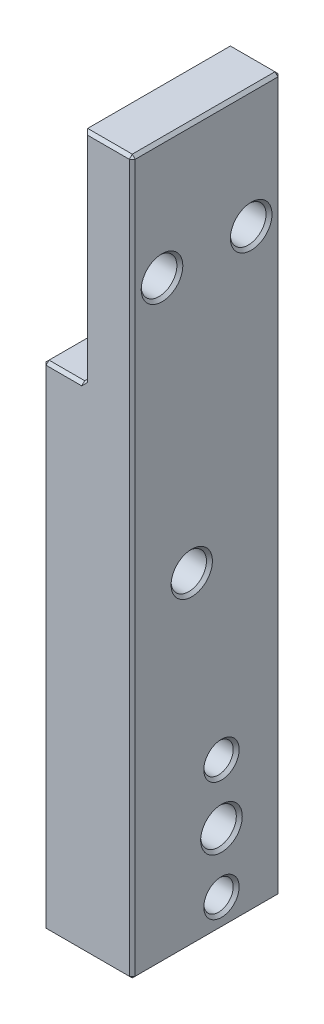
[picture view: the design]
ISO-10303-21;
HEADER;
FILE_DESCRIPTION(('STEP AP214'),'2;1');
FILE_NAME('part.step','',(''),(''),'','','');
FILE_SCHEMA(('AUTOMOTIVE_DESIGN { 1 0 10303 214 1 1 1 1 }'));
ENDSEC;
DATA;
#1=APPLICATION_CONTEXT('core data for automotive mechanical design processes');
#2=APPLICATION_PROTOCOL_DEFINITION('international standard','automotive_design',2000,#1);
#3=PRODUCT_CONTEXT('',#1,'mechanical');
#4=PRODUCT('Part','Part','',(#3));
#5=PRODUCT_RELATED_PRODUCT_CATEGORY('part','',(#4));
#6=PRODUCT_DEFINITION_FORMATION('','',#4);
#7=PRODUCT_DEFINITION_CONTEXT('part definition',#1,'design');
#8=PRODUCT_DEFINITION('design','',#6,#7);
#9=PRODUCT_DEFINITION_SHAPE('','',#8);
#10=(LENGTH_UNIT() NAMED_UNIT(*) SI_UNIT(.MILLI.,.METRE.));
#11=(NAMED_UNIT(*) PLANE_ANGLE_UNIT() SI_UNIT($,.RADIAN.));
#12=(NAMED_UNIT(*) SI_UNIT($,.STERADIAN.) SOLID_ANGLE_UNIT());
#13=UNCERTAINTY_MEASURE_WITH_UNIT(LENGTH_MEASURE(1.E-05),#10,'distance_accuracy_value','');
#14=(GEOMETRIC_REPRESENTATION_CONTEXT(3) GLOBAL_UNCERTAINTY_ASSIGNED_CONTEXT((#13)) GLOBAL_UNIT_ASSIGNED_CONTEXT((#10,
#11,#12)) REPRESENTATION_CONTEXT('',''));
#15=CARTESIAN_POINT('',(0.,0.,0.));
#16=DIRECTION('',(0.,0.,1.));
#17=DIRECTION('',(1.,0.,0.));
#18=AXIS2_PLACEMENT_3D('',#15,#16,#17);
#19=CARTESIAN_POINT('',(0.,0.,25.));
#20=DIRECTION('',(-1.,0.,0.));
#21=DIRECTION('',(0.,0.,1.));
#22=AXIS2_PLACEMENT_3D('',#19,#20,#21);
#23=PLANE('',#22);
#24=CARTESIAN_POINT('',(0.,54.5,15.));
#25=DIRECTION('',(-1.,0.,0.));
#26=DIRECTION('',(0.,0.,1.));
#27=AXIS2_PLACEMENT_3D('',#24,#25,#26);
#28=CIRCLE('',#27,3.475);
#29=CARTESIAN_POINT('',(0.,54.5,18.475));
#30=VERTEX_POINT('',#29);
#31=EDGE_CURVE('E311',#30,#30,#28,.F.);
#32=ORIENTED_EDGE('',*,*,#31,.T.);
#33=EDGE_LOOP('',(#32));
#34=FACE_BOUND('',#33,.T.);
#35=CARTESIAN_POINT('',(0.,24.8,10.));
#36=DIRECTION('',(-1.,0.,0.));
#37=DIRECTION('',(0.,0.,1.));
#38=AXIS2_PLACEMENT_3D('',#35,#36,#37);
#39=CIRCLE('',#38,2.975);
#40=CARTESIAN_POINT('',(0.,24.8,12.975));
#41=VERTEX_POINT('',#40);
#42=EDGE_CURVE('E308',#41,#41,#39,.F.);
#43=ORIENTED_EDGE('',*,*,#42,.T.);
#44=EDGE_LOOP('',(#43));
#45=FACE_BOUND('',#44,.T.);
#46=CARTESIAN_POINT('',(0.,14.8,10.));
#47=DIRECTION('',(-1.,0.,0.));
#48=DIRECTION('',(0.,0.,1.));
#49=AXIS2_PLACEMENT_3D('',#46,#47,#48);
#50=CIRCLE('',#49,3.5);
#51=CARTESIAN_POINT('',(0.,14.8,13.5));
#52=VERTEX_POINT('',#51);
#53=EDGE_CURVE('E305',#52,#52,#50,.F.);
#54=ORIENTED_EDGE('',*,*,#53,.T.);
#55=EDGE_LOOP('',(#54));
#56=FACE_BOUND('',#55,.T.);
#57=CARTESIAN_POINT('',(0.,4.8,10.));
#58=DIRECTION('',(-1.,0.,0.));
#59=DIRECTION('',(0.,0.,1.));
#60=AXIS2_PLACEMENT_3D('',#57,#58,#59);
#61=CIRCLE('',#60,2.975);
#62=CARTESIAN_POINT('',(0.,4.8,12.975));
#63=VERTEX_POINT('',#62);
#64=EDGE_CURVE('E302',#63,#63,#61,.F.);
#65=ORIENTED_EDGE('',*,*,#64,.T.);
#66=EDGE_LOOP('',(#65));
#67=FACE_BOUND('',#66,.T.);
#68=DIRECTION('',(0.,-1.,0.));
#69=VECTOR('',#68,1.);
#70=CARTESIAN_POINT('',(0.,0.,0.500000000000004));
#71=LINE('',#70,#69);
#72=CARTESIAN_POINT('',(0.,82.5,0.500000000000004));
#73=VERTEX_POINT('',#72);
#74=CARTESIAN_POINT('',(0.,0.500000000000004,0.500000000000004));
#75=VERTEX_POINT('',#74);
#76=EDGE_CURVE('E297',#73,#75,#71,.T.);
#77=ORIENTED_EDGE('',*,*,#76,.T.);
#78=DIRECTION('',(0.,0.,1.));
#79=VECTOR('',#78,1.);
#80=CARTESIAN_POINT('',(0.,0.500000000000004,25.));
#81=LINE('',#80,#79);
#82=CARTESIAN_POINT('',(0.,0.500000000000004,24.5));
#83=VERTEX_POINT('',#82);
#84=EDGE_CURVE('E300',#75,#83,#81,.T.);
#85=ORIENTED_EDGE('',*,*,#84,.T.);
#86=DIRECTION('',(0.,1.,0.));
#87=VECTOR('',#86,1.);
#88=CARTESIAN_POINT('',(0.,0.,24.5));
#89=LINE('',#88,#87);
#90=CARTESIAN_POINT('',(0.,82.5,24.5));
#91=VERTEX_POINT('',#90);
#92=EDGE_CURVE('E295',#83,#91,#89,.T.);
#93=ORIENTED_EDGE('',*,*,#92,.T.);
#94=DIRECTION('',(0.,0.,-1.));
#95=VECTOR('',#94,1.);
#96=CARTESIAN_POINT('',(0.,82.5,0.));
#97=LINE('',#96,#95);
#98=EDGE_CURVE('E293',#91,#73,#97,.T.);
#99=ORIENTED_EDGE('',*,*,#98,.T.);
#100=EDGE_LOOP('',(#77,#85,#93,#99));
#101=FACE_BOUND('',#100,.T.);
#102=ADVANCED_FACE('F34',(#34,#45,#56,#67,#101),#23,.T.);
#103=CARTESIAN_POINT('',(0.,0.,25.));
#104=DIRECTION('',(0.,1.,0.));
#105=DIRECTION('',(0.,0.,1.));
#106=AXIS2_PLACEMENT_3D('',#103,#104,#105);
#107=PLANE('',#106);
#108=DIRECTION('',(1.,0.,0.));
#109=VECTOR('',#108,1.);
#110=CARTESIAN_POINT('',(0.,0.,0.500000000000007));
#111=LINE('',#110,#109);
#112=CARTESIAN_POINT('',(0.500000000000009,0.,0.500000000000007));
#113=VERTEX_POINT('',#112);
#114=CARTESIAN_POINT('',(14.5,0.,0.500000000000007));
#115=VERTEX_POINT('',#114);
#116=EDGE_CURVE('E219',#113,#115,#111,.T.);
#117=ORIENTED_EDGE('',*,*,#116,.T.);
#118=DIRECTION('',(0.,0.,1.));
#119=VECTOR('',#118,1.);
#120=CARTESIAN_POINT('',(14.5,0.,25.));
#121=LINE('',#120,#119);
#122=CARTESIAN_POINT('',(14.5,0.,24.5));
#123=VERTEX_POINT('',#122);
#124=EDGE_CURVE('E166',#115,#123,#121,.T.);
#125=ORIENTED_EDGE('',*,*,#124,.T.);
#126=DIRECTION('',(-1.,0.,0.));
#127=VECTOR('',#126,1.);
#128=CARTESIAN_POINT('',(0.,0.,24.5));
#129=LINE('',#128,#127);
#130=CARTESIAN_POINT('',(0.500000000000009,0.,24.5));
#131=VERTEX_POINT('',#130);
#132=EDGE_CURVE('E221',#123,#131,#129,.T.);
#133=ORIENTED_EDGE('',*,*,#132,.T.);
#134=DIRECTION('',(0.,0.,-1.));
#135=VECTOR('',#134,1.);
#136=CARTESIAN_POINT('',(0.500000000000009,0.,0.));
#137=LINE('',#136,#135);
#138=EDGE_CURVE('E217',#131,#113,#137,.T.);
#139=ORIENTED_EDGE('',*,*,#138,.T.);
#140=EDGE_LOOP('',(#117,#125,#133,#139));
#141=FACE_BOUND('',#140,.T.);
#142=ADVANCED_FACE('F36',(#141),#107,.F.);
#143=CARTESIAN_POINT('',(15.,120.,25.));
#144=DIRECTION('',(1.,0.,0.));
#145=DIRECTION('',(0.,1.,0.));
#146=AXIS2_PLACEMENT_3D('',#143,#144,#145);
#147=PLANE('',#146);
#148=CARTESIAN_POINT('',(15.,100.,20.));
#149=DIRECTION('',(1.,0.,0.));
#150=DIRECTION('',(0.,1.,0.));
#151=AXIS2_PLACEMENT_3D('',#148,#149,#150);
#152=CIRCLE('',#151,3.5);
#153=CARTESIAN_POINT('',(15.,103.5,20.));
#154=VERTEX_POINT('',#153);
#155=EDGE_CURVE('E214',#154,#154,#152,.F.);
#156=ORIENTED_EDGE('',*,*,#155,.T.);
#157=EDGE_LOOP('',(#156));
#158=FACE_BOUND('',#157,.T.);
#159=CARTESIAN_POINT('',(15.,100.,5.));
#160=DIRECTION('',(1.,0.,0.));
#161=DIRECTION('',(0.,1.,0.));
#162=AXIS2_PLACEMENT_3D('',#159,#160,#161);
#163=CIRCLE('',#162,3.5);
#164=CARTESIAN_POINT('',(15.,103.5,5.));
#165=VERTEX_POINT('',#164);
#166=EDGE_CURVE('E211',#165,#165,#163,.F.);
#167=ORIENTED_EDGE('',*,*,#166,.T.);
#168=EDGE_LOOP('',(#167));
#169=FACE_BOUND('',#168,.T.);
#170=CARTESIAN_POINT('',(15.,54.5,15.));
#171=DIRECTION('',(1.,0.,0.));
#172=DIRECTION('',(0.,1.,0.));
#173=AXIS2_PLACEMENT_3D('',#170,#171,#172);
#174=CIRCLE('',#173,3.47500000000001);
#175=CARTESIAN_POINT('',(15.,57.975,15.));
#176=VERTEX_POINT('',#175);
#177=EDGE_CURVE('E208',#176,#176,#174,.F.);
#178=ORIENTED_EDGE('',*,*,#177,.T.);
#179=EDGE_LOOP('',(#178));
#180=FACE_BOUND('',#179,.T.);
#181=CARTESIAN_POINT('',(15.,24.8,10.));
#182=DIRECTION('',(1.,0.,0.));
#183=DIRECTION('',(0.,1.,0.));
#184=AXIS2_PLACEMENT_3D('',#181,#182,#183);
#185=CIRCLE('',#184,2.97500000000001);
#186=CARTESIAN_POINT('',(15.,27.775,10.));
#187=VERTEX_POINT('',#186);
#188=EDGE_CURVE('E205',#187,#187,#185,.F.);
#189=ORIENTED_EDGE('',*,*,#188,.T.);
#190=EDGE_LOOP('',(#189));
#191=FACE_BOUND('',#190,.T.);
#192=CARTESIAN_POINT('',(15.,14.8,10.));
#193=DIRECTION('',(1.,0.,0.));
#194=DIRECTION('',(0.,1.,0.));
#195=AXIS2_PLACEMENT_3D('',#192,#193,#194);
#196=CIRCLE('',#195,3.50000000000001);
#197=CARTESIAN_POINT('',(15.,18.3,10.));
#198=VERTEX_POINT('',#197);
#199=EDGE_CURVE('E202',#198,#198,#196,.F.);
#200=ORIENTED_EDGE('',*,*,#199,.T.);
#201=EDGE_LOOP('',(#200));
#202=FACE_BOUND('',#201,.T.);
#203=CARTESIAN_POINT('',(15.,4.8,10.));
#204=DIRECTION('',(1.,0.,0.));
#205=DIRECTION('',(0.,1.,0.));
#206=AXIS2_PLACEMENT_3D('',#203,#204,#205);
#207=CIRCLE('',#206,2.975);
#208=CARTESIAN_POINT('',(15.,7.775,10.));
#209=VERTEX_POINT('',#208);
#210=EDGE_CURVE('E196',#209,#209,#207,.F.);
#211=ORIENTED_EDGE('',*,*,#210,.T.);
#212=EDGE_LOOP('',(#211));
#213=FACE_BOUND('',#212,.T.);
#214=DIRECTION('',(0.,0.,1.));
#215=VECTOR('',#214,1.);
#216=CARTESIAN_POINT('',(15.,119.5,25.));
#217=LINE('',#216,#215);
#218=CARTESIAN_POINT('',(15.,119.5,0.500000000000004));
#219=VERTEX_POINT('',#218);
#220=CARTESIAN_POINT('',(15.,119.5,24.5));
#221=VERTEX_POINT('',#220);
#222=EDGE_CURVE('E188',#219,#221,#217,.T.);
#223=ORIENTED_EDGE('',*,*,#222,.T.);
#224=DIRECTION('',(0.,-1.,0.));
#225=VECTOR('',#224,1.);
#226=CARTESIAN_POINT('',(15.,120.,24.5));
#227=LINE('',#226,#225);
#228=CARTESIAN_POINT('',(15.,0.500000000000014,24.5));
#229=VERTEX_POINT('',#228);
#230=EDGE_CURVE('E193',#221,#229,#227,.T.);
#231=ORIENTED_EDGE('',*,*,#230,.T.);
#232=DIRECTION('',(0.,0.,-1.));
#233=VECTOR('',#232,1.);
#234=CARTESIAN_POINT('',(15.,0.500000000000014,0.));
#235=LINE('',#234,#233);
#236=CARTESIAN_POINT('',(15.,0.500000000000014,0.500000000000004));
#237=VERTEX_POINT('',#236);
#238=EDGE_CURVE('E164',#229,#237,#235,.T.);
#239=ORIENTED_EDGE('',*,*,#238,.T.);
#240=DIRECTION('',(0.,1.,0.));
#241=VECTOR('',#240,1.);
#242=CARTESIAN_POINT('',(15.,120.,0.500000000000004));
#243=LINE('',#242,#241);
#244=EDGE_CURVE('E182',#237,#219,#243,.T.);
#245=ORIENTED_EDGE('',*,*,#244,.T.);
#246=EDGE_LOOP('',(#223,#231,#239,#245));
#247=FACE_BOUND('',#246,.T.);
#248=ADVANCED_FACE('F191',(#158,#169,#180,#191,#202,#213,#247),#147,.T.);
#249=CARTESIAN_POINT('',(7.00000000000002,120.,25.));
#250=DIRECTION('',(0.,1.,0.));
#251=DIRECTION('',(0.,0.,1.));
#252=AXIS2_PLACEMENT_3D('',#249,#250,#251);
#253=PLANE('',#252);
#254=DIRECTION('',(0.,0.,-1.));
#255=VECTOR('',#254,1.);
#256=CARTESIAN_POINT('',(7.00000000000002,120.,25.));
#257=LINE('',#256,#255);
#258=CARTESIAN_POINT('',(7.00000000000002,120.,24.5));
#259=VERTEX_POINT('',#258);
#260=CARTESIAN_POINT('',(7.00000000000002,120.,0.500000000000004));
#261=VERTEX_POINT('',#260);
#262=EDGE_CURVE('E189',#259,#261,#257,.T.);
#263=ORIENTED_EDGE('',*,*,#262,.F.);
#264=DIRECTION('',(1.,0.,0.));
#265=VECTOR('',#264,1.);
#266=CARTESIAN_POINT('',(7.00000000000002,120.,24.5));
#267=LINE('',#266,#265);
#268=CARTESIAN_POINT('',(14.5,120.,24.5));
#269=VERTEX_POINT('',#268);
#270=EDGE_CURVE('E229',#259,#269,#267,.T.);
#271=ORIENTED_EDGE('',*,*,#270,.T.);
#272=DIRECTION('',(0.,0.,-1.));
#273=VECTOR('',#272,1.);
#274=CARTESIAN_POINT('',(14.5,120.,25.));
#275=LINE('',#274,#273);
#276=CARTESIAN_POINT('',(14.5,120.,0.500000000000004));
#277=VERTEX_POINT('',#276);
#278=EDGE_CURVE('E226',#269,#277,#275,.T.);
#279=ORIENTED_EDGE('',*,*,#278,.T.);
#280=DIRECTION('',(-1.,0.,0.));
#281=VECTOR('',#280,1.);
#282=CARTESIAN_POINT('',(7.00000000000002,120.,0.500000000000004));
#283=LINE('',#282,#281);
#284=EDGE_CURVE('E224',#277,#261,#283,.T.);
#285=ORIENTED_EDGE('',*,*,#284,.T.);
#286=EDGE_LOOP('',(#263,#271,#279,#285));
#287=FACE_BOUND('',#286,.T.);
#288=ADVANCED_FACE('F360',(#287),#253,.T.);
#289=CARTESIAN_POINT('',(7.00000000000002,83.,25.));
#290=DIRECTION('',(-1.,0.,0.));
#291=DIRECTION('',(0.,0.,1.));
#292=AXIS2_PLACEMENT_3D('',#289,#290,#291);
#293=PLANE('',#292);
#294=CARTESIAN_POINT('',(7.00000000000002,100.,20.));
#295=DIRECTION('',(-1.,0.,0.));
#296=DIRECTION('',(0.,0.,1.));
#297=AXIS2_PLACEMENT_3D('',#294,#295,#296);
#298=CIRCLE('',#297,3.5);
#299=CARTESIAN_POINT('',(7.00000000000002,100.,23.5));
#300=VERTEX_POINT('',#299);
#301=EDGE_CURVE('E11',#300,#300,#298,.F.);
#302=ORIENTED_EDGE('',*,*,#301,.T.);
#303=EDGE_LOOP('',(#302));
#304=FACE_BOUND('',#303,.T.);
#305=CARTESIAN_POINT('',(7.00000000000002,100.,5.));
#306=DIRECTION('',(-1.,0.,0.));
#307=DIRECTION('',(0.,0.,1.));
#308=AXIS2_PLACEMENT_3D('',#305,#306,#307);
#309=CIRCLE('',#308,3.);
#310=CARTESIAN_POINT('',(7.00000000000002,100.,8.));
#311=VERTEX_POINT('',#310);
#312=EDGE_CURVE('E458',#311,#311,#309,.T.);
#313=ORIENTED_EDGE('',*,*,#312,.F.);
#314=EDGE_LOOP('',(#313));
#315=FACE_BOUND('',#314,.T.);
#316=DIRECTION('',(0.,0.,1.));
#317=VECTOR('',#316,1.);
#318=CARTESIAN_POINT('',(7.00000000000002,83.5,25.));
#319=LINE('',#318,#317);
#320=CARTESIAN_POINT('',(7.00000000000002,83.5,0.500000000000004));
#321=VERTEX_POINT('',#320);
#322=CARTESIAN_POINT('',(7.00000000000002,83.5,24.5));
#323=VERTEX_POINT('',#322);
#324=EDGE_CURVE('E261',#321,#323,#319,.T.);
#325=ORIENTED_EDGE('',*,*,#324,.T.);
#326=DIRECTION('',(0.,1.,0.));
#327=VECTOR('',#326,1.);
#328=CARTESIAN_POINT('',(7.00000000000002,83.,24.5));
#329=LINE('',#328,#327);
#330=EDGE_CURVE('E265',#323,#259,#329,.T.);
#331=ORIENTED_EDGE('',*,*,#330,.T.);
#332=ORIENTED_EDGE('',*,*,#262,.T.);
#333=DIRECTION('',(0.,-1.,0.));
#334=VECTOR('',#333,1.);
#335=CARTESIAN_POINT('',(7.00000000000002,83.,0.500000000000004));
#336=LINE('',#335,#334);
#337=EDGE_CURVE('E263',#261,#321,#336,.T.);
#338=ORIENTED_EDGE('',*,*,#337,.T.);
#339=EDGE_LOOP('',(#325,#331,#332,#338));
#340=FACE_BOUND('',#339,.T.);
#341=ADVANCED_FACE('F356',(#304,#315,#340),#293,.T.);
#342=CARTESIAN_POINT('',(7.00000000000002,83.,25.));
#343=DIRECTION('',(0.,-1.,0.));
#344=DIRECTION('',(0.,0.,-1.));
#345=AXIS2_PLACEMENT_3D('',#342,#343,#344);
#346=PLANE('',#345);
#347=DIRECTION('',(-1.,0.,0.));
#348=VECTOR('',#347,1.);
#349=CARTESIAN_POINT('',(7.00000000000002,83.,0.500000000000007));
#350=LINE('',#349,#348);
#351=CARTESIAN_POINT('',(6.50000000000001,83.,0.500000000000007));
#352=VERTEX_POINT('',#351);
#353=CARTESIAN_POINT('',(0.500000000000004,83.,0.500000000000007));
#354=VERTEX_POINT('',#353);
#355=EDGE_CURVE('E49',#352,#354,#350,.T.);
#356=ORIENTED_EDGE('',*,*,#355,.T.);
#357=DIRECTION('',(0.,0.,1.));
#358=VECTOR('',#357,1.);
#359=CARTESIAN_POINT('',(0.500000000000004,83.,25.));
#360=LINE('',#359,#358);
#361=CARTESIAN_POINT('',(0.500000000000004,83.,24.5));
#362=VERTEX_POINT('',#361);
#363=EDGE_CURVE('E318',#354,#362,#360,.T.);
#364=ORIENTED_EDGE('',*,*,#363,.T.);
#365=DIRECTION('',(1.,0.,0.));
#366=VECTOR('',#365,1.);
#367=CARTESIAN_POINT('',(7.00000000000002,83.,24.5));
#368=LINE('',#367,#366);
#369=CARTESIAN_POINT('',(6.50000000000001,83.,24.5));
#370=VERTEX_POINT('',#369);
#371=EDGE_CURVE('E314',#362,#370,#368,.T.);
#372=ORIENTED_EDGE('',*,*,#371,.T.);
#373=DIRECTION('',(0.,0.,-1.));
#374=VECTOR('',#373,1.);
#375=CARTESIAN_POINT('',(6.50000000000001,83.,25.));
#376=LINE('',#375,#374);
#377=EDGE_CURVE('E54',#370,#352,#376,.T.);
#378=ORIENTED_EDGE('',*,*,#377,.T.);
#379=EDGE_LOOP('',(#356,#364,#372,#378));
#380=FACE_BOUND('',#379,.T.);
#381=ADVANCED_FACE('F353',(#380),#346,.F.);
#382=CARTESIAN_POINT('',(0.,83.,25.));
#383=DIRECTION('',(0.,0.,1.));
#384=DIRECTION('',(1.,0.,0.));
#385=AXIS2_PLACEMENT_3D('',#382,#383,#384);
#386=PLANE('',#385);
#387=DIRECTION('',(0.,-1.,0.));
#388=VECTOR('',#387,1.);
#389=CARTESIAN_POINT('',(7.50000000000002,83.,25.));
#390=LINE('',#389,#388);
#391=CARTESIAN_POINT('',(7.50000000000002,119.5,25.));
#392=VERTEX_POINT('',#391);
#393=CARTESIAN_POINT('',(7.50000000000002,83.5,25.));
#394=VERTEX_POINT('',#393);
#395=EDGE_CURVE('E277',#392,#394,#390,.T.);
#396=ORIENTED_EDGE('',*,*,#395,.T.);
#397=DIRECTION('',(0.707106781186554,0.707106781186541,0.));
#398=VECTOR('',#397,1.);
#399=CARTESIAN_POINT('',(3.49999999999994,79.5,25.));
#400=LINE('',#399,#398);
#401=CARTESIAN_POINT('',(6.50000000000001,82.5,25.));
#402=VERTEX_POINT('',#401);
#403=EDGE_CURVE('E320',#394,#402,#400,.F.);
#404=ORIENTED_EDGE('',*,*,#403,.T.);
#405=DIRECTION('',(-1.,0.,0.));
#406=VECTOR('',#405,1.);
#407=CARTESIAN_POINT('',(0.,82.5,25.));
#408=LINE('',#407,#406);
#409=CARTESIAN_POINT('',(0.500000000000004,82.5,25.));
#410=VERTEX_POINT('',#409);
#411=EDGE_CURVE('E267',#402,#410,#408,.T.);
#412=ORIENTED_EDGE('',*,*,#411,.T.);
#413=DIRECTION('',(0.,-1.,0.));
#414=VECTOR('',#413,1.);
#415=CARTESIAN_POINT('',(0.500000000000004,83.,25.));
#416=LINE('',#415,#414);
#417=CARTESIAN_POINT('',(0.500000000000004,0.500000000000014,25.));
#418=VERTEX_POINT('',#417);
#419=EDGE_CURVE('E269',#410,#418,#416,.T.);
#420=ORIENTED_EDGE('',*,*,#419,.T.);
#421=DIRECTION('',(1.,0.,0.));
#422=VECTOR('',#421,1.);
#423=CARTESIAN_POINT('',(15.,0.500000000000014,25.));
#424=LINE('',#423,#422);
#425=CARTESIAN_POINT('',(14.5,0.500000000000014,25.));
#426=VERTEX_POINT('',#425);
#427=EDGE_CURVE('E271',#418,#426,#424,.T.);
#428=ORIENTED_EDGE('',*,*,#427,.T.);
#429=DIRECTION('',(0.,1.,0.));
#430=VECTOR('',#429,1.);
#431=CARTESIAN_POINT('',(14.5,83.,25.));
#432=LINE('',#431,#430);
#433=CARTESIAN_POINT('',(14.5,119.5,25.));
#434=VERTEX_POINT('',#433);
#435=EDGE_CURVE('E273',#426,#434,#432,.T.);
#436=ORIENTED_EDGE('',*,*,#435,.T.);
#437=DIRECTION('',(-1.,0.,0.));
#438=VECTOR('',#437,1.);
#439=CARTESIAN_POINT('',(0.,119.5,25.));
#440=LINE('',#439,#438);
#441=EDGE_CURVE('E275',#434,#392,#440,.T.);
#442=ORIENTED_EDGE('',*,*,#441,.T.);
#443=EDGE_LOOP('',(#396,#404,#412,#420,#428,#436,#442));
#444=FACE_BOUND('',#443,.T.);
#445=ADVANCED_FACE('F351',(#444),#386,.T.);
#446=CARTESIAN_POINT('',(0.,83.,0.));
#447=DIRECTION('',(0.,0.,1.));
#448=DIRECTION('',(1.,0.,0.));
#449=AXIS2_PLACEMENT_3D('',#446,#447,#448);
#450=PLANE('',#449);
#451=DIRECTION('',(1.,0.,0.));
#452=VECTOR('',#451,1.);
#453=CARTESIAN_POINT('',(0.,82.5,0.));
#454=LINE('',#453,#452);
#455=CARTESIAN_POINT('',(0.500000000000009,82.5,0.));
#456=VERTEX_POINT('',#455);
#457=CARTESIAN_POINT('',(6.50000000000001,82.5,0.));
#458=VERTEX_POINT('',#457);
#459=EDGE_CURVE('E280',#456,#458,#454,.T.);
#460=ORIENTED_EDGE('',*,*,#459,.T.);
#461=DIRECTION('',(-0.707106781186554,-0.707106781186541,0.));
#462=VECTOR('',#461,1.);
#463=CARTESIAN_POINT('',(6.5,82.5,0.));
#464=LINE('',#463,#462);
#465=CARTESIAN_POINT('',(7.50000000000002,83.5,0.));
#466=VERTEX_POINT('',#465);
#467=EDGE_CURVE('E322',#458,#466,#464,.F.);
#468=ORIENTED_EDGE('',*,*,#467,.T.);
#469=DIRECTION('',(0.,1.,0.));
#470=VECTOR('',#469,1.);
#471=CARTESIAN_POINT('',(7.50000000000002,120.,0.));
#472=LINE('',#471,#470);
#473=CARTESIAN_POINT('',(7.50000000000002,119.5,0.));
#474=VERTEX_POINT('',#473);
#475=EDGE_CURVE('E291',#466,#474,#472,.T.);
#476=ORIENTED_EDGE('',*,*,#475,.T.);
#477=DIRECTION('',(1.,0.,0.));
#478=VECTOR('',#477,1.);
#479=CARTESIAN_POINT('',(15.,119.5,0.));
#480=LINE('',#479,#478);
#481=CARTESIAN_POINT('',(14.5,119.5,0.));
#482=VERTEX_POINT('',#481);
#483=EDGE_CURVE('E289',#474,#482,#480,.T.);
#484=ORIENTED_EDGE('',*,*,#483,.T.);
#485=DIRECTION('',(0.,-1.,0.));
#486=VECTOR('',#485,1.);
#487=CARTESIAN_POINT('',(14.5,0.,0.));
#488=LINE('',#487,#486);
#489=CARTESIAN_POINT('',(14.5,0.5,0.));
#490=VERTEX_POINT('',#489);
#491=EDGE_CURVE('E287',#482,#490,#488,.T.);
#492=ORIENTED_EDGE('',*,*,#491,.T.);
#493=DIRECTION('',(-1.,0.,0.));
#494=VECTOR('',#493,1.);
#495=CARTESIAN_POINT('',(0.,0.5,0.));
#496=LINE('',#495,#494);
#497=CARTESIAN_POINT('',(0.500000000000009,0.5,0.));
#498=VERTEX_POINT('',#497);
#499=EDGE_CURVE('E284',#490,#498,#496,.T.);
#500=ORIENTED_EDGE('',*,*,#499,.T.);
#501=DIRECTION('',(0.,1.,0.));
#502=VECTOR('',#501,1.);
#503=CARTESIAN_POINT('',(0.500000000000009,83.,0.));
#504=LINE('',#503,#502);
#505=EDGE_CURVE('E282',#498,#456,#504,.T.);
#506=ORIENTED_EDGE('',*,*,#505,.T.);
#507=EDGE_LOOP('',(#460,#468,#476,#484,#492,#500,#506));
#508=FACE_BOUND('',#507,.T.);
#509=ADVANCED_FACE('F357',(#508),#450,.F.);
#510=CARTESIAN_POINT('',(-9.99999999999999,100.,20.));
#511=DIRECTION('',(1.,0.,0.));
#512=DIRECTION('',(0.,1.,0.));
#513=AXIS2_PLACEMENT_3D('',#510,#511,#512);
#514=CYLINDRICAL_SURFACE('',#513,3.);
#515=CARTESIAN_POINT('',(7.50000000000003,100.,20.));
#516=DIRECTION('',(-1.,0.,0.));
#517=DIRECTION('',(0.,0.,1.));
#518=AXIS2_PLACEMENT_3D('',#515,#516,#517);
#519=CIRCLE('',#518,3.);
#520=CARTESIAN_POINT('',(7.50000000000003,100.,23.));
#521=VERTEX_POINT('',#520);
#522=EDGE_CURVE('E42',#521,#521,#519,.T.);
#523=ORIENTED_EDGE('',*,*,#522,.T.);
#524=EDGE_LOOP('',(#523));
#525=FACE_BOUND('',#524,.T.);
#526=CARTESIAN_POINT('',(14.5,100.,20.));
#527=DIRECTION('',(1.,0.,0.));
#528=DIRECTION('',(0.,0.,-1.));
#529=AXIS2_PLACEMENT_3D('',#526,#527,#528);
#530=CIRCLE('',#529,3.);
#531=CARTESIAN_POINT('',(14.5,100.,17.));
#532=VERTEX_POINT('',#531);
#533=EDGE_CURVE('E231',#532,#532,#530,.T.);
#534=ORIENTED_EDGE('',*,*,#533,.T.);
#535=EDGE_LOOP('',(#534));
#536=FACE_BOUND('',#535,.T.);
#537=ADVANCED_FACE('F326',(#525,#536),#514,.F.);
#538=CARTESIAN_POINT('',(-9.99999999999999,100.,5.));
#539=DIRECTION('',(1.,0.,0.));
#540=DIRECTION('',(0.,1.,0.));
#541=AXIS2_PLACEMENT_3D('',#538,#539,#540);
#542=CYLINDRICAL_SURFACE('',#541,3.);
#543=CARTESIAN_POINT('',(14.5,100.,5.));
#544=DIRECTION('',(1.,0.,0.));
#545=DIRECTION('',(0.,0.,-1.));
#546=AXIS2_PLACEMENT_3D('',#543,#544,#545);
#547=CIRCLE('',#546,3.);
#548=CARTESIAN_POINT('',(14.5,100.,2.));
#549=VERTEX_POINT('',#548);
#550=EDGE_CURVE('E234',#549,#549,#547,.T.);
#551=ORIENTED_EDGE('',*,*,#550,.T.);
#552=EDGE_LOOP('',(#551));
#553=FACE_BOUND('',#552,.T.);
#554=ORIENTED_EDGE('',*,*,#312,.T.);
#555=EDGE_LOOP('',(#554));
#556=FACE_BOUND('',#555,.T.);
#557=ADVANCED_FACE('F414',(#553,#556),#542,.F.);
#558=CARTESIAN_POINT('',(-9.99999999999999,54.5,15.));
#559=DIRECTION('',(1.,0.,0.));
#560=DIRECTION('',(0.,1.,0.));
#561=AXIS2_PLACEMENT_3D('',#558,#559,#560);
#562=CYLINDRICAL_SURFACE('',#561,2.975);
#563=CARTESIAN_POINT('',(14.5,54.5,15.));
#564=DIRECTION('',(1.,0.,0.));
#565=DIRECTION('',(0.,0.,-1.));
#566=AXIS2_PLACEMENT_3D('',#563,#564,#565);
#567=CIRCLE('',#566,2.975);
#568=CARTESIAN_POINT('',(14.5,54.5,12.025));
#569=VERTEX_POINT('',#568);
#570=EDGE_CURVE('E240',#569,#569,#567,.T.);
#571=ORIENTED_EDGE('',*,*,#570,.T.);
#572=EDGE_LOOP('',(#571));
#573=FACE_BOUND('',#572,.T.);
#574=CARTESIAN_POINT('',(0.500000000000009,54.5,15.));
#575=DIRECTION('',(-1.,0.,0.));
#576=DIRECTION('',(0.,0.,1.));
#577=AXIS2_PLACEMENT_3D('',#574,#575,#576);
#578=CIRCLE('',#577,2.975);
#579=CARTESIAN_POINT('',(0.500000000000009,54.5,17.975));
#580=VERTEX_POINT('',#579);
#581=EDGE_CURVE('E237',#580,#580,#578,.T.);
#582=ORIENTED_EDGE('',*,*,#581,.T.);
#583=EDGE_LOOP('',(#582));
#584=FACE_BOUND('',#583,.T.);
#585=ADVANCED_FACE('F410',(#573,#584),#562,.F.);
#586=CARTESIAN_POINT('',(-10.,24.8,10.));
#587=DIRECTION('',(1.,0.,0.));
#588=DIRECTION('',(0.,1.,0.));
#589=AXIS2_PLACEMENT_3D('',#586,#587,#588);
#590=CYLINDRICAL_SURFACE('',#589,2.475);
#591=CARTESIAN_POINT('',(14.5,24.8,10.));
#592=DIRECTION('',(1.,0.,0.));
#593=DIRECTION('',(0.,0.,-1.));
#594=AXIS2_PLACEMENT_3D('',#591,#592,#593);
#595=CIRCLE('',#594,2.475);
#596=CARTESIAN_POINT('',(14.5,24.8,7.525));
#597=VERTEX_POINT('',#596);
#598=EDGE_CURVE('E246',#597,#597,#595,.T.);
#599=ORIENTED_EDGE('',*,*,#598,.T.);
#600=EDGE_LOOP('',(#599));
#601=FACE_BOUND('',#600,.T.);
#602=CARTESIAN_POINT('',(0.500000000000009,24.8,10.));
#603=DIRECTION('',(-1.,0.,0.));
#604=DIRECTION('',(0.,0.,1.));
#605=AXIS2_PLACEMENT_3D('',#602,#603,#604);
#606=CIRCLE('',#605,2.475);
#607=CARTESIAN_POINT('',(0.500000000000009,24.8,12.475));
#608=VERTEX_POINT('',#607);
#609=EDGE_CURVE('E243',#608,#608,#606,.T.);
#610=ORIENTED_EDGE('',*,*,#609,.T.);
#611=EDGE_LOOP('',(#610));
#612=FACE_BOUND('',#611,.T.);
#613=ADVANCED_FACE('F403',(#601,#612),#590,.F.);
#614=CARTESIAN_POINT('',(-10.,14.8,10.));
#615=DIRECTION('',(1.,0.,0.));
#616=DIRECTION('',(0.,1.,0.));
#617=AXIS2_PLACEMENT_3D('',#614,#615,#616);
#618=CYLINDRICAL_SURFACE('',#617,3.);
#619=CARTESIAN_POINT('',(14.5,14.8,10.));
#620=DIRECTION('',(1.,0.,0.));
#621=DIRECTION('',(0.,0.,-1.));
#622=AXIS2_PLACEMENT_3D('',#619,#620,#621);
#623=CIRCLE('',#622,3.);
#624=CARTESIAN_POINT('',(14.5,14.8,7.));
#625=VERTEX_POINT('',#624);
#626=EDGE_CURVE('E252',#625,#625,#623,.T.);
#627=ORIENTED_EDGE('',*,*,#626,.T.);
#628=EDGE_LOOP('',(#627));
#629=FACE_BOUND('',#628,.T.);
#630=CARTESIAN_POINT('',(0.500000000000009,14.8,10.));
#631=DIRECTION('',(-1.,0.,0.));
#632=DIRECTION('',(0.,-1.,0.));
#633=AXIS2_PLACEMENT_3D('',#630,#631,#632);
#634=CIRCLE('',#633,3.);
#635=CARTESIAN_POINT('',(0.499999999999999,11.8,10.));
#636=VERTEX_POINT('',#635);
#637=EDGE_CURVE('E249',#636,#636,#634,.T.);
#638=ORIENTED_EDGE('',*,*,#637,.T.);
#639=EDGE_LOOP('',(#638));
#640=FACE_BOUND('',#639,.T.);
#641=ADVANCED_FACE('F392',(#629,#640),#618,.F.);
#642=CARTESIAN_POINT('',(-10.,4.8,10.));
#643=DIRECTION('',(1.,0.,0.));
#644=DIRECTION('',(0.,1.,0.));
#645=AXIS2_PLACEMENT_3D('',#642,#643,#644);
#646=CYLINDRICAL_SURFACE('',#645,2.475);
#647=CARTESIAN_POINT('',(14.5,4.8,10.));
#648=DIRECTION('',(1.,0.,0.));
#649=DIRECTION('',(0.,0.,-1.));
#650=AXIS2_PLACEMENT_3D('',#647,#648,#649);
#651=CIRCLE('',#650,2.475);
#652=CARTESIAN_POINT('',(14.5,4.8,7.525));
#653=VERTEX_POINT('',#652);
#654=EDGE_CURVE('E258',#653,#653,#651,.T.);
#655=ORIENTED_EDGE('',*,*,#654,.T.);
#656=EDGE_LOOP('',(#655));
#657=FACE_BOUND('',#656,.T.);
#658=CARTESIAN_POINT('',(0.500000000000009,4.8,10.));
#659=DIRECTION('',(-1.,0.,0.));
#660=DIRECTION('',(0.,0.,1.));
#661=AXIS2_PLACEMENT_3D('',#658,#659,#660);
#662=CIRCLE('',#661,2.475);
#663=CARTESIAN_POINT('',(0.500000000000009,4.8,12.475));
#664=VERTEX_POINT('',#663);
#665=EDGE_CURVE('E255',#664,#664,#662,.T.);
#666=ORIENTED_EDGE('',*,*,#665,.T.);
#667=EDGE_LOOP('',(#666));
#668=FACE_BOUND('',#667,.T.);
#669=ADVANCED_FACE('F388',(#657,#668),#646,.F.);
#670=CARTESIAN_POINT('',(6.50000000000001,83.,25.));
#671=DIRECTION('',(0.707106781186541,-0.707106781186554,0.));
#672=DIRECTION('',(0.707106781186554,0.707106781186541,0.));
#673=AXIS2_PLACEMENT_3D('',#670,#671,#672);
#674=PLANE('',#673);
#675=DIRECTION('',(0.707106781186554,0.707106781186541,0.));
#676=VECTOR('',#675,1.);
#677=CARTESIAN_POINT('',(6.50000000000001,83.,0.500000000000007));
#678=LINE('',#677,#676);
#679=EDGE_CURVE('E443',#352,#321,#678,.T.);
#680=ORIENTED_EDGE('',*,*,#679,.F.);
#681=ORIENTED_EDGE('',*,*,#377,.F.);
#682=DIRECTION('',(-0.707106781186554,-0.707106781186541,0.));
#683=VECTOR('',#682,1.);
#684=CARTESIAN_POINT('',(6.50000000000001,83.,24.5));
#685=LINE('',#684,#683);
#686=EDGE_CURVE('E446',#323,#370,#685,.T.);
#687=ORIENTED_EDGE('',*,*,#686,.F.);
#688=ORIENTED_EDGE('',*,*,#324,.F.);
#689=EDGE_LOOP('',(#680,#681,#687,#688));
#690=FACE_BOUND('',#689,.T.);
#691=ADVANCED_FACE('F391',(#690),#674,.F.);
#692=CARTESIAN_POINT('',(0.,82.5,25.));
#693=DIRECTION('',(0.,0.70710678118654,0.707106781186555));
#694=DIRECTION('',(0.,-0.707106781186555,0.70710678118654));
#695=AXIS2_PLACEMENT_3D('',#692,#693,#694);
#696=PLANE('',#695);
#697=DIRECTION('',(0.,0.707106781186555,-0.70710678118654));
#698=VECTOR('',#697,1.);
#699=CARTESIAN_POINT('',(0.500000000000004,82.75,24.75));
#700=LINE('',#699,#698);
#701=EDGE_CURVE('E449',#410,#362,#700,.T.);
#702=ORIENTED_EDGE('',*,*,#701,.F.);
#703=ORIENTED_EDGE('',*,*,#411,.F.);
#704=DIRECTION('',(0.,-0.707106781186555,0.70710678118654));
#705=VECTOR('',#704,1.);
#706=CARTESIAN_POINT('',(6.50000000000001,83.,24.5));
#707=LINE('',#706,#705);
#708=EDGE_CURVE('E455',#370,#402,#707,.T.);
#709=ORIENTED_EDGE('',*,*,#708,.F.);
#710=ORIENTED_EDGE('',*,*,#371,.F.);
#711=EDGE_LOOP('',(#702,#703,#709,#710));
#712=FACE_BOUND('',#711,.T.);
#713=ADVANCED_FACE('F400',(#712),#696,.T.);
#714=CARTESIAN_POINT('',(7.00000000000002,83.5,24.5));
#715=DIRECTION('',(-0.577350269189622,0.577350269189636,0.577350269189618));
#716=DIRECTION('',(-0.707106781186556,-0.707106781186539,0.));
#717=AXIS2_PLACEMENT_3D('',#714,#715,#716);
#718=PLANE('',#717);
#719=ORIENTED_EDGE('',*,*,#708,.T.);
#720=ORIENTED_EDGE('',*,*,#403,.F.);
#721=DIRECTION('',(-0.707106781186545,0.,-0.70710678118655));
#722=VECTOR('',#721,1.);
#723=CARTESIAN_POINT('',(7.50000000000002,83.5,25.));
#724=LINE('',#723,#722);
#725=EDGE_CURVE('E475',#323,#394,#724,.F.);
#726=ORIENTED_EDGE('',*,*,#725,.F.);
#727=ORIENTED_EDGE('',*,*,#686,.T.);
#728=EDGE_LOOP('',(#719,#720,#726,#727));
#729=FACE_BOUND('',#728,.T.);
#730=ADVANCED_FACE('F476',(#729),#718,.T.);
#731=CARTESIAN_POINT('',(6.50000000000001,83.,0.500000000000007));
#732=DIRECTION('',(-0.577350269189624,0.577350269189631,-0.577350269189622));
#733=DIRECTION('',(-0.707106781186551,-0.707106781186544,0.));
#734=AXIS2_PLACEMENT_3D('',#731,#732,#733);
#735=PLANE('',#734);
#736=DIRECTION('',(0.707106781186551,0.,-0.707106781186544));
#737=VECTOR('',#736,1.);
#738=CARTESIAN_POINT('',(7.00000000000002,83.5,0.500000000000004));
#739=LINE('',#738,#737);
#740=EDGE_CURVE('E440',#466,#321,#739,.F.);
#741=ORIENTED_EDGE('',*,*,#740,.F.);
#742=ORIENTED_EDGE('',*,*,#467,.F.);
#743=DIRECTION('',(0.,0.707106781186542,0.707106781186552));
#744=VECTOR('',#743,1.);
#745=CARTESIAN_POINT('',(6.50000000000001,82.5,0.));
#746=LINE('',#745,#744);
#747=EDGE_CURVE('E438',#352,#458,#746,.F.);
#748=ORIENTED_EDGE('',*,*,#747,.F.);
#749=ORIENTED_EDGE('',*,*,#679,.T.);
#750=EDGE_LOOP('',(#741,#742,#748,#749));
#751=FACE_BOUND('',#750,.T.);
#752=ADVANCED_FACE('F436',(#751),#735,.T.);
#753=CARTESIAN_POINT('',(7.00000000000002,83.,0.500000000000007));
#754=DIRECTION('',(0.,-0.707106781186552,0.707106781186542));
#755=DIRECTION('',(0.,-0.707106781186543,-0.707106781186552));
#756=AXIS2_PLACEMENT_3D('',#753,#754,#755);
#757=PLANE('',#756);
#758=ORIENTED_EDGE('',*,*,#747,.T.);
#759=ORIENTED_EDGE('',*,*,#459,.F.);
#760=DIRECTION('',(0.,0.707106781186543,0.707106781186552));
#761=VECTOR('',#760,1.);
#762=CARTESIAN_POINT('',(0.500000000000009,82.5,0.));
#763=LINE('',#762,#761);
#764=EDGE_CURVE('E516',#354,#456,#763,.F.);
#765=ORIENTED_EDGE('',*,*,#764,.F.);
#766=ORIENTED_EDGE('',*,*,#355,.F.);
#767=EDGE_LOOP('',(#758,#759,#765,#766));
#768=FACE_BOUND('',#767,.T.);
#769=ADVANCED_FACE('F442',(#768),#757,.F.);
#770=CARTESIAN_POINT('',(0.,82.5,25.));
#771=DIRECTION('',(-0.707106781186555,0.70710678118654,0.));
#772=DIRECTION('',(-0.70710678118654,-0.707106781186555,0.));
#773=AXIS2_PLACEMENT_3D('',#770,#771,#772);
#774=PLANE('',#773);
#775=DIRECTION('',(-0.70710678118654,-0.707106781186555,0.));
#776=VECTOR('',#775,1.);
#777=CARTESIAN_POINT('',(0.,82.5,24.5));
#778=LINE('',#777,#776);
#779=EDGE_CURVE('E444',#362,#91,#778,.T.);
#780=ORIENTED_EDGE('',*,*,#779,.F.);
#781=ORIENTED_EDGE('',*,*,#363,.F.);
#782=DIRECTION('',(0.70710678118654,0.707106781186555,0.));
#783=VECTOR('',#782,1.);
#784=CARTESIAN_POINT('',(0.250000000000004,82.75,0.500000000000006));
#785=LINE('',#784,#783);
#786=EDGE_CURVE('E518',#73,#354,#785,.T.);
#787=ORIENTED_EDGE('',*,*,#786,.F.);
#788=ORIENTED_EDGE('',*,*,#98,.F.);
#789=EDGE_LOOP('',(#780,#781,#787,#788));
#790=FACE_BOUND('',#789,.T.);
#791=ADVANCED_FACE('F533',(#790),#774,.T.);
#792=CARTESIAN_POINT('',(0.,82.5,24.5));
#793=DIRECTION('',(-0.577350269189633,0.577350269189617,0.577350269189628));
#794=DIRECTION('',(0.707106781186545,0.,0.70710678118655));
#795=AXIS2_PLACEMENT_3D('',#792,#793,#794);
#796=PLANE('',#795);
#797=ORIENTED_EDGE('',*,*,#701,.T.);
#798=ORIENTED_EDGE('',*,*,#779,.T.);
#799=DIRECTION('',(-0.707106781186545,0.,-0.70710678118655));
#800=VECTOR('',#799,1.);
#801=CARTESIAN_POINT('',(0.,82.5,24.5));
#802=LINE('',#801,#800);
#803=EDGE_CURVE('E487',#410,#91,#802,.T.);
#804=ORIENTED_EDGE('',*,*,#803,.F.);
#805=EDGE_LOOP('',(#797,#798,#804));
#806=FACE_BOUND('',#805,.T.);
#807=ADVANCED_FACE('F525',(#806),#796,.T.);
#808=CARTESIAN_POINT('',(7.00000000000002,83.,24.5));
#809=DIRECTION('',(0.70710678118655,0.,-0.707106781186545));
#810=DIRECTION('',(-0.707106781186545,0.,-0.70710678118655));
#811=AXIS2_PLACEMENT_3D('',#808,#809,#810);
#812=PLANE('',#811);
#813=ORIENTED_EDGE('',*,*,#725,.T.);
#814=ORIENTED_EDGE('',*,*,#395,.F.);
#815=DIRECTION('',(0.577350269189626,-0.577350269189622,0.57735026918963));
#816=VECTOR('',#815,1.);
#817=CARTESIAN_POINT('',(7.00000000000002,120.,24.5));
#818=LINE('',#817,#816);
#819=EDGE_CURVE('E483',#259,#392,#818,.T.);
#820=ORIENTED_EDGE('',*,*,#819,.F.);
#821=ORIENTED_EDGE('',*,*,#330,.F.);
#822=EDGE_LOOP('',(#813,#814,#820,#821));
#823=FACE_BOUND('',#822,.T.);
#824=ADVANCED_FACE('F481',(#823),#812,.F.);
#825=CARTESIAN_POINT('',(7.50000000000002,83.,0.));
#826=DIRECTION('',(-0.707106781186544,0.,-0.707106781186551));
#827=DIRECTION('',(-0.707106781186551,0.,0.707106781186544));
#828=AXIS2_PLACEMENT_3D('',#825,#826,#827);
#829=PLANE('',#828);
#830=ORIENTED_EDGE('',*,*,#740,.T.);
#831=ORIENTED_EDGE('',*,*,#337,.F.);
#832=DIRECTION('',(0.577350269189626,-0.577350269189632,-0.57735026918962));
#833=VECTOR('',#832,1.);
#834=CARTESIAN_POINT('',(19.6666666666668,107.333333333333,-12.1666666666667));
#835=LINE('',#834,#833);
#836=EDGE_CURVE('E488',#474,#261,#835,.F.);
#837=ORIENTED_EDGE('',*,*,#836,.F.);
#838=ORIENTED_EDGE('',*,*,#475,.F.);
#839=EDGE_LOOP('',(#830,#831,#837,#838));
#840=FACE_BOUND('',#839,.T.);
#841=ADVANCED_FACE('F515',(#840),#829,.T.);
#842=CARTESIAN_POINT('',(0.500000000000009,82.5,0.));
#843=DIRECTION('',(-0.577350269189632,0.577350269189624,-0.577350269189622));
#844=DIRECTION('',(-0.707106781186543,-0.707106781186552,0.));
#845=AXIS2_PLACEMENT_3D('',#842,#843,#844);
#846=PLANE('',#845);
#847=ORIENTED_EDGE('',*,*,#786,.T.);
#848=ORIENTED_EDGE('',*,*,#764,.T.);
#849=DIRECTION('',(-0.707106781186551,0.,0.707106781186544));
#850=VECTOR('',#849,1.);
#851=CARTESIAN_POINT('',(0.500000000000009,82.5,0.));
#852=LINE('',#851,#850);
#853=EDGE_CURVE('E566',#73,#456,#852,.F.);
#854=ORIENTED_EDGE('',*,*,#853,.F.);
#855=EDGE_LOOP('',(#847,#848,#854));
#856=FACE_BOUND('',#855,.T.);
#857=ADVANCED_FACE('F573',(#856),#846,.T.);
#858=CARTESIAN_POINT('',(0.,0.,24.5));
#859=DIRECTION('',(0.70710678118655,0.,-0.707106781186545));
#860=DIRECTION('',(-0.707106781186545,0.,-0.70710678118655));
#861=AXIS2_PLACEMENT_3D('',#858,#859,#860);
#862=PLANE('',#861);
#863=ORIENTED_EDGE('',*,*,#803,.T.);
#864=ORIENTED_EDGE('',*,*,#92,.F.);
#865=DIRECTION('',(0.707106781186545,0.,0.70710678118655));
#866=VECTOR('',#865,1.);
#867=CARTESIAN_POINT('',(0.249999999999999,0.500000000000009,24.75));
#868=LINE('',#867,#866);
#869=EDGE_CURVE('E541',#418,#83,#868,.F.);
#870=ORIENTED_EDGE('',*,*,#869,.F.);
#871=ORIENTED_EDGE('',*,*,#419,.F.);
#872=EDGE_LOOP('',(#863,#864,#870,#871));
#873=FACE_BOUND('',#872,.T.);
#874=ADVANCED_FACE('F583',(#873),#862,.F.);
#875=CARTESIAN_POINT('',(7.00000000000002,120.,24.5));
#876=DIRECTION('',(0.,-0.707106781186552,-0.707106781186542));
#877=DIRECTION('',(0.,0.707106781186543,-0.707106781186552));
#878=AXIS2_PLACEMENT_3D('',#875,#876,#877);
#879=PLANE('',#878);
#880=ORIENTED_EDGE('',*,*,#819,.T.);
#881=ORIENTED_EDGE('',*,*,#441,.F.);
#882=DIRECTION('',(0.,0.707106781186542,-0.707106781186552));
#883=VECTOR('',#882,1.);
#884=CARTESIAN_POINT('',(14.5,119.75,24.75));
#885=LINE('',#884,#883);
#886=EDGE_CURVE('E493',#269,#434,#885,.F.);
#887=ORIENTED_EDGE('',*,*,#886,.F.);
#888=ORIENTED_EDGE('',*,*,#270,.F.);
#889=EDGE_LOOP('',(#880,#881,#887,#888));
#890=FACE_BOUND('',#889,.T.);
#891=ADVANCED_FACE('F491',(#890),#879,.F.);
#892=CARTESIAN_POINT('',(14.5,120.,25.));
#893=DIRECTION('',(-0.707106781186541,-0.707106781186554,0.));
#894=DIRECTION('',(0.707106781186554,-0.707106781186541,0.));
#895=AXIS2_PLACEMENT_3D('',#892,#893,#894);
#896=PLANE('',#895);
#897=DIRECTION('',(-0.707106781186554,0.707106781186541,0.));
#898=VECTOR('',#897,1.);
#899=CARTESIAN_POINT('',(14.5,120.,0.500000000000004));
#900=LINE('',#899,#898);
#901=EDGE_CURVE('E503',#277,#219,#900,.F.);
#902=ORIENTED_EDGE('',*,*,#901,.F.);
#903=ORIENTED_EDGE('',*,*,#278,.F.);
#904=DIRECTION('',(0.707106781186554,-0.707106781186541,0.));
#905=VECTOR('',#904,1.);
#906=CARTESIAN_POINT('',(15.,119.5,24.5));
#907=LINE('',#906,#905);
#908=EDGE_CURVE('E500',#221,#269,#907,.F.);
#909=ORIENTED_EDGE('',*,*,#908,.F.);
#910=ORIENTED_EDGE('',*,*,#222,.F.);
#911=EDGE_LOOP('',(#902,#903,#909,#910));
#912=FACE_BOUND('',#911,.T.);
#913=ADVANCED_FACE('F499',(#912),#896,.F.);
#914=CARTESIAN_POINT('',(0.,119.5,0.));
#915=DIRECTION('',(0.,0.70710678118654,-0.707106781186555));
#916=DIRECTION('',(0.,0.707106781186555,0.70710678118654));
#917=AXIS2_PLACEMENT_3D('',#914,#915,#916);
#918=PLANE('',#917);
#919=ORIENTED_EDGE('',*,*,#836,.T.);
#920=ORIENTED_EDGE('',*,*,#284,.F.);
#921=DIRECTION('',(0.,0.707106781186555,0.70710678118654));
#922=VECTOR('',#921,1.);
#923=CARTESIAN_POINT('',(14.5,120.,0.500000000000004));
#924=LINE('',#923,#922);
#925=EDGE_CURVE('E506',#482,#277,#924,.T.);
#926=ORIENTED_EDGE('',*,*,#925,.F.);
#927=ORIENTED_EDGE('',*,*,#483,.F.);
#928=EDGE_LOOP('',(#919,#920,#926,#927));
#929=FACE_BOUND('',#928,.T.);
#930=ADVANCED_FACE('F511',(#929),#918,.T.);
#931=CARTESIAN_POINT('',(0.500000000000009,83.,0.));
#932=DIRECTION('',(-0.707106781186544,0.,-0.707106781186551));
#933=DIRECTION('',(-0.707106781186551,0.,0.707106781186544));
#934=AXIS2_PLACEMENT_3D('',#931,#932,#933);
#935=PLANE('',#934);
#936=ORIENTED_EDGE('',*,*,#853,.T.);
#937=ORIENTED_EDGE('',*,*,#505,.F.);
#938=DIRECTION('',(0.707106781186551,0.,-0.707106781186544));
#939=VECTOR('',#938,1.);
#940=CARTESIAN_POINT('',(0.500000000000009,0.5,0.));
#941=LINE('',#940,#939);
#942=EDGE_CURVE('E556',#75,#498,#941,.T.);
#943=ORIENTED_EDGE('',*,*,#942,.F.);
#944=ORIENTED_EDGE('',*,*,#76,.F.);
#945=EDGE_LOOP('',(#936,#937,#943,#944));
#946=FACE_BOUND('',#945,.T.);
#947=ADVANCED_FACE('F577',(#946),#935,.T.);
#948=CARTESIAN_POINT('',(0.500000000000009,0.,25.));
#949=DIRECTION('',(-0.707106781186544,-0.707106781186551,0.));
#950=DIRECTION('',(0.707106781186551,-0.707106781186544,0.));
#951=AXIS2_PLACEMENT_3D('',#948,#949,#950);
#952=PLANE('',#951);
#953=DIRECTION('',(0.707106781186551,-0.707106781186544,0.));
#954=VECTOR('',#953,1.);
#955=CARTESIAN_POINT('',(0.500000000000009,0.,24.5));
#956=LINE('',#955,#954);
#957=EDGE_CURVE('E563',#83,#131,#956,.T.);
#958=ORIENTED_EDGE('',*,*,#957,.F.);
#959=ORIENTED_EDGE('',*,*,#84,.F.);
#960=DIRECTION('',(-0.707106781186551,0.707106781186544,0.));
#961=VECTOR('',#960,1.);
#962=CARTESIAN_POINT('',(0.250000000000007,0.249999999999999,0.500000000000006));
#963=LINE('',#962,#961);
#964=EDGE_CURVE('E549',#113,#75,#963,.T.);
#965=ORIENTED_EDGE('',*,*,#964,.F.);
#966=ORIENTED_EDGE('',*,*,#138,.F.);
#967=EDGE_LOOP('',(#958,#959,#965,#966));
#968=FACE_BOUND('',#967,.T.);
#969=ADVANCED_FACE('F587',(#968),#952,.T.);
#970=CARTESIAN_POINT('',(0.500000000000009,0.,24.5));
#971=DIRECTION('',(-0.577350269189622,-0.577350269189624,0.577350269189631));
#972=DIRECTION('',(0.,-0.707106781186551,-0.707106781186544));
#973=AXIS2_PLACEMENT_3D('',#970,#971,#972);
#974=PLANE('',#973);
#975=ORIENTED_EDGE('',*,*,#869,.T.);
#976=ORIENTED_EDGE('',*,*,#957,.T.);
#977=DIRECTION('',(0.,0.707106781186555,0.70710678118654));
#978=VECTOR('',#977,1.);
#979=CARTESIAN_POINT('',(0.500000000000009,0.,24.5));
#980=LINE('',#979,#978);
#981=EDGE_CURVE('E546',#418,#131,#980,.F.);
#982=ORIENTED_EDGE('',*,*,#981,.F.);
#983=EDGE_LOOP('',(#975,#976,#982));
#984=FACE_BOUND('',#983,.T.);
#985=ADVANCED_FACE('F590',(#984),#974,.T.);
#986=CARTESIAN_POINT('',(15.,119.5,24.5));
#987=DIRECTION('',(0.577350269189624,0.577350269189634,0.57735026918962));
#988=DIRECTION('',(-0.707106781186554,0.707106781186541,0.));
#989=AXIS2_PLACEMENT_3D('',#986,#987,#988);
#990=PLANE('',#989);
#991=ORIENTED_EDGE('',*,*,#908,.T.);
#992=ORIENTED_EDGE('',*,*,#886,.T.);
#993=DIRECTION('',(-0.707106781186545,0.,0.70710678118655));
#994=VECTOR('',#993,1.);
#995=CARTESIAN_POINT('',(15.,119.5,24.5));
#996=LINE('',#995,#994);
#997=EDGE_CURVE('E540',#221,#434,#996,.T.);
#998=ORIENTED_EDGE('',*,*,#997,.F.);
#999=EDGE_LOOP('',(#991,#992,#998));
#1000=FACE_BOUND('',#999,.T.);
#1001=ADVANCED_FACE('F539',(#1000),#990,.T.);
#1002=CARTESIAN_POINT('',(14.5,120.,0.500000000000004));
#1003=DIRECTION('',(0.577350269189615,0.577350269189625,-0.577350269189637));
#1004=DIRECTION('',(0.,0.707106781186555,0.70710678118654));
#1005=AXIS2_PLACEMENT_3D('',#1002,#1003,#1004);
#1006=PLANE('',#1005);
#1007=ORIENTED_EDGE('',*,*,#925,.T.);
#1008=ORIENTED_EDGE('',*,*,#901,.T.);
#1009=DIRECTION('',(-0.707106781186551,0.,-0.707106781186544));
#1010=VECTOR('',#1009,1.);
#1011=CARTESIAN_POINT('',(14.75,119.5,0.250000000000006));
#1012=LINE('',#1011,#1010);
#1013=EDGE_CURVE('E185',#482,#219,#1012,.F.);
#1014=ORIENTED_EDGE('',*,*,#1013,.F.);
#1015=EDGE_LOOP('',(#1007,#1008,#1014));
#1016=FACE_BOUND('',#1015,.T.);
#1017=ADVANCED_FACE('F612',(#1016),#1006,.T.);
#1018=CARTESIAN_POINT('',(0.500000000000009,0.5,0.));
#1019=DIRECTION('',(-0.577350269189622,-0.577350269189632,-0.577350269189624));
#1020=DIRECTION('',(0.,0.707106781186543,-0.707106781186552));
#1021=AXIS2_PLACEMENT_3D('',#1018,#1019,#1020);
#1022=PLANE('',#1021);
#1023=ORIENTED_EDGE('',*,*,#964,.T.);
#1024=ORIENTED_EDGE('',*,*,#942,.T.);
#1025=DIRECTION('',(0.,0.707106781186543,-0.707106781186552));
#1026=VECTOR('',#1025,1.);
#1027=CARTESIAN_POINT('',(0.500000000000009,0.5,0.));
#1028=LINE('',#1027,#1026);
#1029=EDGE_CURVE('E551',#113,#498,#1028,.T.);
#1030=ORIENTED_EDGE('',*,*,#1029,.F.);
#1031=EDGE_LOOP('',(#1023,#1024,#1030));
#1032=FACE_BOUND('',#1031,.T.);
#1033=ADVANCED_FACE('F610',(#1032),#1022,.T.);
#1034=CARTESIAN_POINT('',(0.,0.500000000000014,25.));
#1035=DIRECTION('',(0.,-0.70710678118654,0.707106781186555));
#1036=DIRECTION('',(0.,-0.707106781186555,-0.70710678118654));
#1037=AXIS2_PLACEMENT_3D('',#1034,#1035,#1036);
#1038=PLANE('',#1037);
#1039=ORIENTED_EDGE('',*,*,#981,.T.);
#1040=ORIENTED_EDGE('',*,*,#132,.F.);
#1041=DIRECTION('',(0.,-0.707106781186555,-0.70710678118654));
#1042=VECTOR('',#1041,1.);
#1043=CARTESIAN_POINT('',(14.5,0.,24.5));
#1044=LINE('',#1043,#1042);
#1045=EDGE_CURVE('E596',#426,#123,#1044,.T.);
#1046=ORIENTED_EDGE('',*,*,#1045,.F.);
#1047=ORIENTED_EDGE('',*,*,#427,.F.);
#1048=EDGE_LOOP('',(#1039,#1040,#1046,#1047));
#1049=FACE_BOUND('',#1048,.T.);
#1050=ADVANCED_FACE('F594',(#1049),#1038,.T.);
#1051=CARTESIAN_POINT('',(15.,120.,24.5));
#1052=DIRECTION('',(-0.70710678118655,0.,-0.707106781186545));
#1053=DIRECTION('',(-0.707106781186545,0.,0.70710678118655));
#1054=AXIS2_PLACEMENT_3D('',#1051,#1052,#1053);
#1055=PLANE('',#1054);
#1056=ORIENTED_EDGE('',*,*,#997,.T.);
#1057=ORIENTED_EDGE('',*,*,#435,.F.);
#1058=DIRECTION('',(0.707106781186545,0.,-0.70710678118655));
#1059=VECTOR('',#1058,1.);
#1060=CARTESIAN_POINT('',(14.75,0.500000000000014,24.75));
#1061=LINE('',#1060,#1059);
#1062=EDGE_CURVE('E179',#229,#426,#1061,.F.);
#1063=ORIENTED_EDGE('',*,*,#1062,.F.);
#1064=ORIENTED_EDGE('',*,*,#230,.F.);
#1065=EDGE_LOOP('',(#1056,#1057,#1063,#1064));
#1066=FACE_BOUND('',#1065,.T.);
#1067=ADVANCED_FACE('F544',(#1066),#1055,.F.);
#1068=CARTESIAN_POINT('',(14.5,83.,0.));
#1069=DIRECTION('',(0.707106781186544,0.,-0.707106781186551));
#1070=DIRECTION('',(-0.707106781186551,0.,-0.707106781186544));
#1071=AXIS2_PLACEMENT_3D('',#1068,#1069,#1070);
#1072=PLANE('',#1071);
#1073=ORIENTED_EDGE('',*,*,#1013,.T.);
#1074=ORIENTED_EDGE('',*,*,#244,.F.);
#1075=DIRECTION('',(0.707106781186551,0.,0.707106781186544));
#1076=VECTOR('',#1075,1.);
#1077=CARTESIAN_POINT('',(15.,0.500000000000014,0.500000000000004));
#1078=LINE('',#1077,#1076);
#1079=EDGE_CURVE('E172',#490,#237,#1078,.T.);
#1080=ORIENTED_EDGE('',*,*,#1079,.F.);
#1081=ORIENTED_EDGE('',*,*,#491,.F.);
#1082=EDGE_LOOP('',(#1073,#1074,#1080,#1081));
#1083=FACE_BOUND('',#1082,.T.);
#1084=ADVANCED_FACE('F183',(#1083),#1072,.T.);
#1085=CARTESIAN_POINT('',(0.,0.,0.500000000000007));
#1086=DIRECTION('',(0.,0.707106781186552,0.707106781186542));
#1087=DIRECTION('',(0.,-0.707106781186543,0.707106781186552));
#1088=AXIS2_PLACEMENT_3D('',#1085,#1086,#1087);
#1089=PLANE('',#1088);
#1090=ORIENTED_EDGE('',*,*,#1029,.T.);
#1091=ORIENTED_EDGE('',*,*,#499,.F.);
#1092=DIRECTION('',(0.,-0.707106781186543,0.707106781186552));
#1093=VECTOR('',#1092,1.);
#1094=CARTESIAN_POINT('',(14.5,0.250000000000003,0.250000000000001));
#1095=LINE('',#1094,#1093);
#1096=EDGE_CURVE('E176',#115,#490,#1095,.F.);
#1097=ORIENTED_EDGE('',*,*,#1096,.F.);
#1098=ORIENTED_EDGE('',*,*,#116,.F.);
#1099=EDGE_LOOP('',(#1090,#1091,#1097,#1098));
#1100=FACE_BOUND('',#1099,.T.);
#1101=ADVANCED_FACE('F608',(#1100),#1089,.F.);
#1102=CARTESIAN_POINT('',(14.5,0.,24.5));
#1103=DIRECTION('',(0.577350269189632,-0.577350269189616,0.577350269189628));
#1104=DIRECTION('',(0.707106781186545,0.,-0.70710678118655));
#1105=AXIS2_PLACEMENT_3D('',#1102,#1103,#1104);
#1106=PLANE('',#1105);
#1107=ORIENTED_EDGE('',*,*,#1062,.T.);
#1108=ORIENTED_EDGE('',*,*,#1045,.T.);
#1109=DIRECTION('',(0.70710678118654,0.707106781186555,0.));
#1110=VECTOR('',#1109,1.);
#1111=CARTESIAN_POINT('',(14.5,0.,24.5));
#1112=LINE('',#1111,#1110);
#1113=EDGE_CURVE('E169',#229,#123,#1112,.F.);
#1114=ORIENTED_EDGE('',*,*,#1113,.F.);
#1115=EDGE_LOOP('',(#1107,#1108,#1114));
#1116=FACE_BOUND('',#1115,.T.);
#1117=ADVANCED_FACE('F601',(#1116),#1106,.T.);
#1118=CARTESIAN_POINT('',(15.,0.500000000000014,0.500000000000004));
#1119=DIRECTION('',(0.577350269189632,-0.577350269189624,-0.577350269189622));
#1120=DIRECTION('',(0.707106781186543,0.707106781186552,0.));
#1121=AXIS2_PLACEMENT_3D('',#1118,#1119,#1120);
#1122=PLANE('',#1121);
#1123=ORIENTED_EDGE('',*,*,#1096,.T.);
#1124=ORIENTED_EDGE('',*,*,#1079,.T.);
#1125=DIRECTION('',(-0.70710678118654,-0.707106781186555,0.));
#1126=VECTOR('',#1125,1.);
#1127=CARTESIAN_POINT('',(15.,0.500000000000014,0.500000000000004));
#1128=LINE('',#1127,#1126);
#1129=EDGE_CURVE('E160',#115,#237,#1128,.F.);
#1130=ORIENTED_EDGE('',*,*,#1129,.F.);
#1131=EDGE_LOOP('',(#1123,#1124,#1130));
#1132=FACE_BOUND('',#1131,.T.);
#1133=ADVANCED_FACE('F174',(#1132),#1122,.T.);
#1134=CARTESIAN_POINT('',(15.,0.500000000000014,25.));
#1135=DIRECTION('',(0.707106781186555,-0.70710678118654,0.));
#1136=DIRECTION('',(0.70710678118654,0.707106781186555,0.));
#1137=AXIS2_PLACEMENT_3D('',#1134,#1135,#1136);
#1138=PLANE('',#1137);
#1139=ORIENTED_EDGE('',*,*,#1113,.T.);
#1140=ORIENTED_EDGE('',*,*,#124,.F.);
#1141=ORIENTED_EDGE('',*,*,#1129,.T.);
#1142=ORIENTED_EDGE('',*,*,#238,.F.);
#1143=EDGE_LOOP('',(#1139,#1140,#1141,#1142));
#1144=FACE_BOUND('',#1143,.T.);
#1145=ADVANCED_FACE('F162',(#1144),#1138,.T.);
#1146=CARTESIAN_POINT('',(14.5,100.,20.));
#1147=DIRECTION('',(1.,0.,0.));
#1148=DIRECTION('',(0.,0.,-1.));
#1149=AXIS2_PLACEMENT_3D('',#1146,#1147,#1148);
#1150=CONICAL_SURFACE('',#1149,3.,0.785398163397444);
#1151=ORIENTED_EDGE('',*,*,#155,.F.);
#1152=EDGE_LOOP('',(#1151));
#1153=FACE_BOUND('',#1152,.T.);
#1154=ORIENTED_EDGE('',*,*,#533,.F.);
#1155=EDGE_LOOP('',(#1154));
#1156=FACE_BOUND('',#1155,.T.);
#1157=ADVANCED_FACE('F784',(#1153,#1156),#1150,.F.);
#1158=CARTESIAN_POINT('',(14.5,100.,5.));
#1159=DIRECTION('',(1.,0.,0.));
#1160=DIRECTION('',(0.,0.,-1.));
#1161=AXIS2_PLACEMENT_3D('',#1158,#1159,#1160);
#1162=CONICAL_SURFACE('',#1161,3.,0.78539816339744);
#1163=ORIENTED_EDGE('',*,*,#166,.F.);
#1164=EDGE_LOOP('',(#1163));
#1165=FACE_BOUND('',#1164,.T.);
#1166=ORIENTED_EDGE('',*,*,#550,.F.);
#1167=EDGE_LOOP('',(#1166));
#1168=FACE_BOUND('',#1167,.T.);
#1169=ADVANCED_FACE('F793',(#1165,#1168),#1162,.F.);
#1170=CARTESIAN_POINT('',(14.5,54.5,15.));
#1171=DIRECTION('',(1.,0.,0.));
#1172=DIRECTION('',(0.,0.,-1.));
#1173=AXIS2_PLACEMENT_3D('',#1170,#1171,#1172);
#1174=CONICAL_SURFACE('',#1173,2.975,0.785398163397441);
#1175=ORIENTED_EDGE('',*,*,#177,.F.);
#1176=EDGE_LOOP('',(#1175));
#1177=FACE_BOUND('',#1176,.T.);
#1178=ORIENTED_EDGE('',*,*,#570,.F.);
#1179=EDGE_LOOP('',(#1178));
#1180=FACE_BOUND('',#1179,.T.);
#1181=ADVANCED_FACE('F803',(#1177,#1180),#1174,.F.);
#1182=CARTESIAN_POINT('',(14.5,24.8,10.));
#1183=DIRECTION('',(1.,0.,0.));
#1184=DIRECTION('',(0.,0.,-1.));
#1185=AXIS2_PLACEMENT_3D('',#1182,#1183,#1184);
#1186=CONICAL_SURFACE('',#1185,2.475,0.785398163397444);
#1187=ORIENTED_EDGE('',*,*,#188,.F.);
#1188=EDGE_LOOP('',(#1187));
#1189=FACE_BOUND('',#1188,.T.);
#1190=ORIENTED_EDGE('',*,*,#598,.F.);
#1191=EDGE_LOOP('',(#1190));
#1192=FACE_BOUND('',#1191,.T.);
#1193=ADVANCED_FACE('F813',(#1189,#1192),#1186,.F.);
#1194=CARTESIAN_POINT('',(14.5,14.8,10.));
#1195=DIRECTION('',(1.,0.,0.));
#1196=DIRECTION('',(0.,0.,-1.));
#1197=AXIS2_PLACEMENT_3D('',#1194,#1195,#1196);
#1198=CONICAL_SURFACE('',#1197,3.,0.785398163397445);
#1199=ORIENTED_EDGE('',*,*,#199,.F.);
#1200=EDGE_LOOP('',(#1199));
#1201=FACE_BOUND('',#1200,.T.);
#1202=ORIENTED_EDGE('',*,*,#626,.F.);
#1203=EDGE_LOOP('',(#1202));
#1204=FACE_BOUND('',#1203,.T.);
#1205=ADVANCED_FACE('F384',(#1201,#1204),#1198,.F.);
#1206=CARTESIAN_POINT('',(14.5,4.8,10.));
#1207=DIRECTION('',(1.,0.,0.));
#1208=DIRECTION('',(0.,0.,-1.));
#1209=AXIS2_PLACEMENT_3D('',#1206,#1207,#1208);
#1210=CONICAL_SURFACE('',#1209,2.475,0.785398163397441);
#1211=ORIENTED_EDGE('',*,*,#210,.F.);
#1212=EDGE_LOOP('',(#1211));
#1213=FACE_BOUND('',#1212,.T.);
#1214=ORIENTED_EDGE('',*,*,#654,.F.);
#1215=EDGE_LOOP('',(#1214));
#1216=FACE_BOUND('',#1215,.T.);
#1217=ADVANCED_FACE('F380',(#1213,#1216),#1210,.F.);
#1218=CARTESIAN_POINT('',(0.500000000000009,54.5,15.));
#1219=DIRECTION('',(-1.,0.,0.));
#1220=DIRECTION('',(0.,0.,1.));
#1221=AXIS2_PLACEMENT_3D('',#1218,#1219,#1220);
#1222=CONICAL_SURFACE('',#1221,2.975,0.785398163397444);
#1223=ORIENTED_EDGE('',*,*,#31,.F.);
#1224=EDGE_LOOP('',(#1223));
#1225=FACE_BOUND('',#1224,.T.);
#1226=ORIENTED_EDGE('',*,*,#581,.F.);
#1227=EDGE_LOOP('',(#1226));
#1228=FACE_BOUND('',#1227,.T.);
#1229=ADVANCED_FACE('F383',(#1225,#1228),#1222,.F.);
#1230=CARTESIAN_POINT('',(0.500000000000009,24.8,10.));
#1231=DIRECTION('',(-1.,0.,0.));
#1232=DIRECTION('',(0.,0.,1.));
#1233=AXIS2_PLACEMENT_3D('',#1230,#1231,#1232);
#1234=CONICAL_SURFACE('',#1233,2.475,0.785398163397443);
#1235=ORIENTED_EDGE('',*,*,#42,.F.);
#1236=EDGE_LOOP('',(#1235));
#1237=FACE_BOUND('',#1236,.T.);
#1238=ORIENTED_EDGE('',*,*,#609,.F.);
#1239=EDGE_LOOP('',(#1238));
#1240=FACE_BOUND('',#1239,.T.);
#1241=ADVANCED_FACE('F847',(#1237,#1240),#1234,.F.);
#1242=CARTESIAN_POINT('',(0.500000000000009,14.8,10.));
#1243=DIRECTION('',(-1.,0.,0.));
#1244=DIRECTION('',(0.,-1.,0.));
#1245=AXIS2_PLACEMENT_3D('',#1242,#1243,#1244);
#1246=CONICAL_SURFACE('',#1245,3.,0.785398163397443);
#1247=ORIENTED_EDGE('',*,*,#53,.F.);
#1248=EDGE_LOOP('',(#1247));
#1249=FACE_BOUND('',#1248,.T.);
#1250=ORIENTED_EDGE('',*,*,#637,.F.);
#1251=EDGE_LOOP('',(#1250));
#1252=FACE_BOUND('',#1251,.T.);
#1253=ADVANCED_FACE('F337',(#1249,#1252),#1246,.F.);
#1254=CARTESIAN_POINT('',(0.500000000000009,4.8,10.));
#1255=DIRECTION('',(-1.,0.,0.));
#1256=DIRECTION('',(0.,0.,1.));
#1257=AXIS2_PLACEMENT_3D('',#1254,#1255,#1256);
#1258=CONICAL_SURFACE('',#1257,2.475,0.785398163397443);
#1259=ORIENTED_EDGE('',*,*,#64,.F.);
#1260=EDGE_LOOP('',(#1259));
#1261=FACE_BOUND('',#1260,.T.);
#1262=ORIENTED_EDGE('',*,*,#665,.F.);
#1263=EDGE_LOOP('',(#1262));
#1264=FACE_BOUND('',#1263,.T.);
#1265=ADVANCED_FACE('F331',(#1261,#1264),#1258,.F.);
#1266=CARTESIAN_POINT('',(7.50000000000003,100.,20.));
#1267=DIRECTION('',(-1.,0.,0.));
#1268=DIRECTION('',(0.,0.,1.));
#1269=AXIS2_PLACEMENT_3D('',#1266,#1267,#1268);
#1270=CONICAL_SURFACE('',#1269,3.,0.785398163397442);
#1271=ORIENTED_EDGE('',*,*,#301,.F.);
#1272=EDGE_LOOP('',(#1271));
#1273=FACE_BOUND('',#1272,.T.);
#1274=ORIENTED_EDGE('',*,*,#522,.F.);
#1275=EDGE_LOOP('',(#1274));
#1276=FACE_BOUND('',#1275,.T.);
#1277=ADVANCED_FACE('F329',(#1273,#1276),#1270,.F.);
#1278=CLOSED_SHELL('',(#102,#142,#248,#288,#341,#381,#445,#509,#537,#557,#585,#613,#641,#669,
#691,#713,#730,#752,#769,#791,#807,#824,#841,#857,#874,#891,#913,#930,#947,#969,#985,#1001,
#1017,#1033,#1050,#1067,#1084,#1101,#1117,#1133,#1145,#1157,#1169,#1181,#1193,#1205,#1217,#1229,
#1241,#1253,#1265,#1277));
#1279=MANIFOLD_SOLID_BREP('B2',#1278);
#1280=ADVANCED_BREP_SHAPE_REPRESENTATION('',(#18,#1279),#14);
#1281=SHAPE_DEFINITION_REPRESENTATION(#9,#1280);
ENDSEC;
END-ISO-10303-21;
